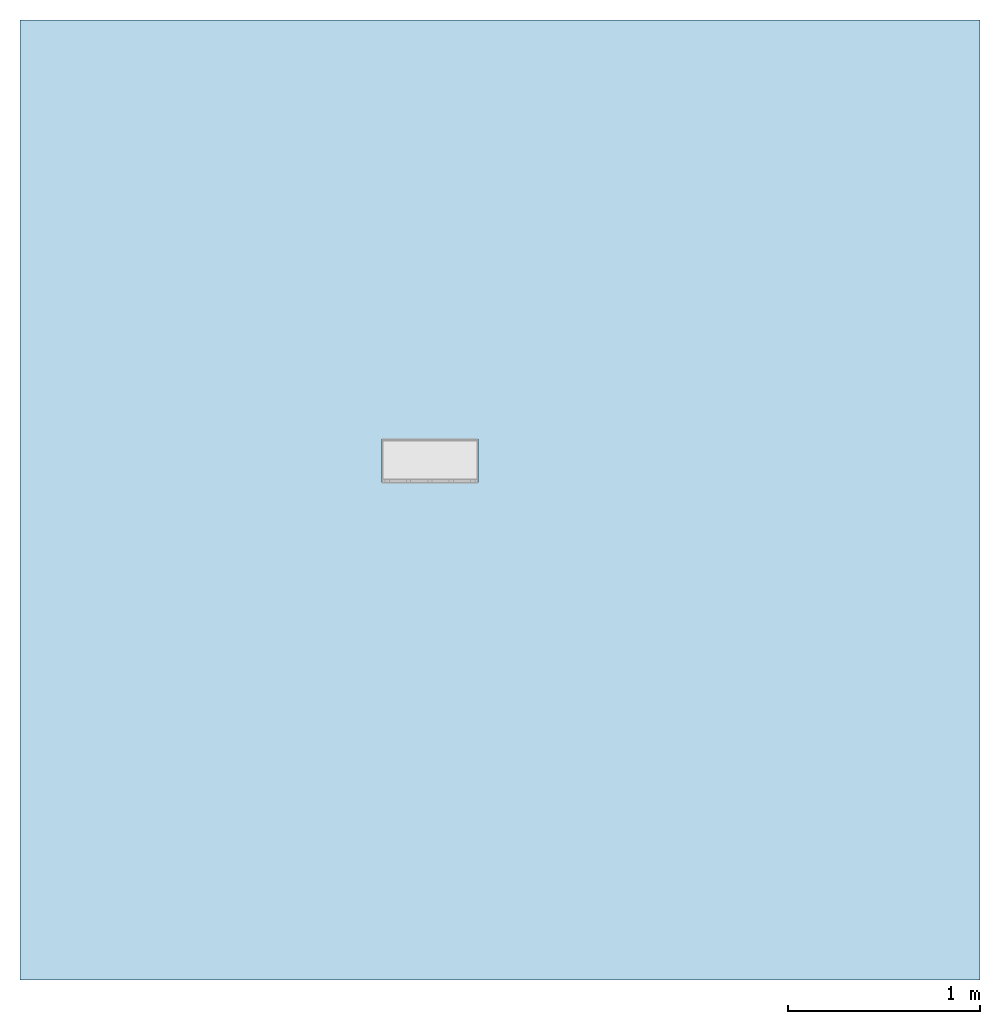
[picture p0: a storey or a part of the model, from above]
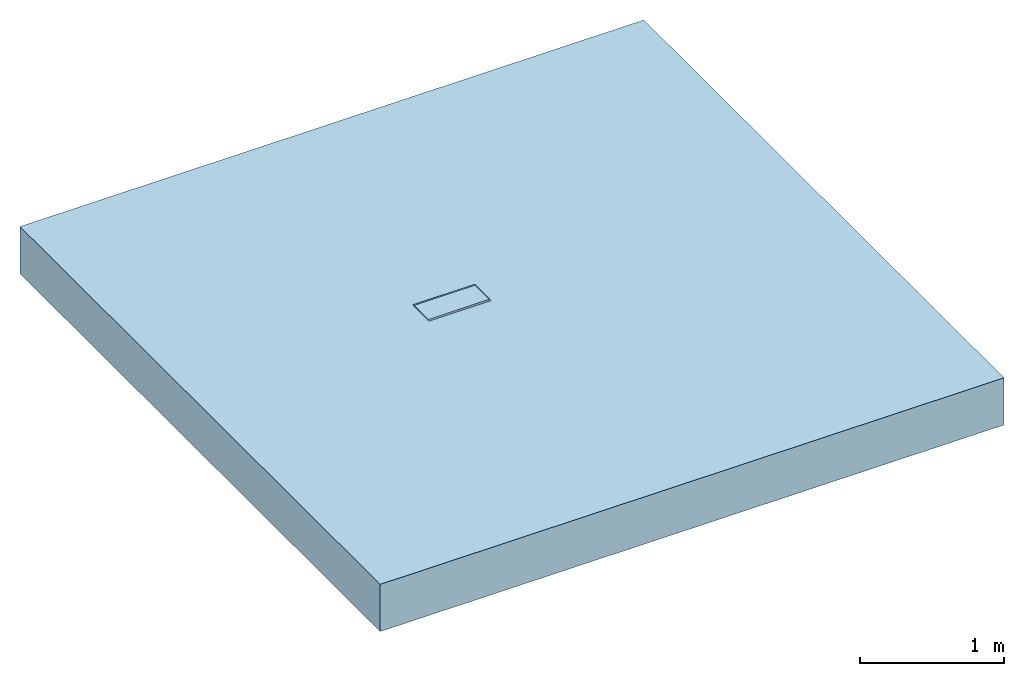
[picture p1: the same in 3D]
Properties of the parts of a building model (IFC2X3)

# File
Description: ViewDefinition [CoordinationView]
File name: 23218 - Universal Sump Unit - 500mm LG.ifc
Time: 2013-10-30T13:50:15
Written by: Autodesk Revit 2013
Made in: 20120221_2030(x64)

# IfcProject, Project Number
LongName: Project Name; Phase: Project Status

# IfcSite, Default
RefLatitude: 42, 21, 30, 344238; RefLongitude: -71, -3, -35, -194702; RefElevation: 0 mm

# IfcBuilding
Pset_BuildingCommon - NumberOfStoreys: 1
Other - Client Name: Owner; Project Name: Project Name; Project Issue Date: Issue Date; Project Number: Project Number; Project Address: ## Street City, State Zip; Project Status: Project Status

# IfcBuildingStorey, Level 1
LongName: Level 1; Elevation: 0 mm
Constraints - Elevation Base: 0; Elevation: 0 mm
Graphics - Color: 0; Symbol at End 1 Default: no; Line Pattern: Center; Symbol: M_Level Head - Circle: M_Level Head - Circle; Line Weight: 1; Symbol at End 2 Default: yes
Dimensions - Computation Height: 0 mm
Identity Data - Structural: no; Name: Level 1; Building Story: yes

# IfcBuildingElementProxy: 23218 - Universal Sump Unit - 500mm LG, Civil-Drainage-Channel-ACO-MultiDrain-M200D-Brickslot-Channel-System:23218 - Universal Sump Unit - 500mm LG:23218 - Universal Sump Unit - 500mm LG:196059
In: Level 1
Material: Plastic, Opaque Black, Steel, Galvanized, Phenolic Resin, Vienite® Synthetic Resin Concrete
Other - CreatedBy: www.aco.co.uk; Revision: 1
Dimensions - Length: 1000 mm; FloorCut_Length: -500 mm; Custom_Void_Length: 500 mm; Volume: 23569804 mm3; Brickslot Access Unit Void Bottom Depth: -105 mm; Brickslot Void Length: -500 mm; Brickslot Grating Void Depth: 6500 mm; Brickslot Access Void Depth: 0 mm; EndCap Position: 500 mm; Length Drain: -1000 mm; FloorCut_Depth: 790 mm; Brickslot Access unit void length: -500 mm; InvDepth: 110 mm; EndCap_Height: 310 mm; FloorCut_HorPosition: 117.5 mm; Depth: 235 mm; FloorCut_Width: 235 mm
Construction - 408995_Load Class C250 & D400_Brickslot Grating_Galvanized Steel_1000mm Long: no; 408997_Load Class C250 & D400_Brickslot_Access Unit_Galvanized Steel_500mm Long: yes; 408996_Load Class C250 & D400_Brickslot Grating_Galvanized Steel_500mm Long: no; 23219 - Universal Endcap (Male End): no; 23219 - Universal Endcap (Female End): no; Constant Depth Channel_500: no; Constant Depth Channel_1000: no; Shallow Depth Channel: no; Shallow Depth Channel with seal: no; 23410_Sump Unit: yes
Constraints - Moves With Nearby Elements: no; Level: Level: Level 1
Phasing - Phase Created: New Construction
Pset_BuildingElementProxyCommon - Reference: 23218 - Universal Sump Unit - 500mm LG
General - TagNumber: 0; SerialNumber: 0
Identity Data - Watermarked By: www.aco.co.uk; Maintenance guidelines: http://www.aco.co.uk/download.php?id=173; Assembly Code: D2040; Product Page URL: http://www.aco.co.uk/product_detail.php?id=58; Model: ACO MultiDrain MD Brickslot - M200D; Product brochure: http://www.aco.co.uk/download.php?id=173; Installation guidelines: http://www.aco.co.uk/download.php?id=173; Fax: +44 (0)1462 815895; Price: POA - contact ACO; OmniClass Title: Rainwater Removal; Watermark 2: This file is water marked and users are prohibited to reproduce, adapt, distribute this information; Watermark 1: This file is the property of ACO Technologies PLC; Address: ACO Business Park, Hitchin Road, Shefford, Bedfordshire, United Kingdom SG17 5TE; Manufacturer: ACO Technologies plc - ACO Water Management Division; Product Code: 23218; Assembly Description: Rain Water Drainage; Watermarked With: BIM Manager Premium Suite; URL: www.aco.co.uk; e-mail Sales: customersupport@aco.co.uk; Cost: 0; e-mail Technical: technical@aco.co.uk; Telephone: +44 (0)1462 816666; Model Description: Channel drainage system; Type Comments: ACO MultiDrain M200D Sump Unit 500mm Long; OmniClass Number: 23.70.50.24
Data - Pre-formed Outlet Ø: 110mm/160mm/200mm; Product Standard: BS EN 1433:2002, CE marked; ACO Hydraulic Design Software: http://www.acodesign.co.uk; Product Dimensions: 500mm x 235mm x 790mm (LxWxH); Product Weight: 47.0 Kg; Load Class: A 15 - D 400; Installation - Concrete Grade: N/A; Channel C.S.A: N/A; Concrete Surround Volume - Load Class B 125 - C 250 - Concrete Pavement: N/A; Hydraulic Performance: http://www.aco.co.uk/download.php?id=173; Concrete Surround Volume - Load Class A 15 - Concrete Pavement: N/A; Concrete Surround Volume - Load Class D 400 - Concrete Pavement: N/A; Invert Depth: 765mm
Green Building Properties - Channel Recyclable: Fully recyclable; Edge Rail Recycled Material Content: Between 40% - 90%; Channel Recycled Material Content: 20% minimum; Edge Rail Recyclable: Fully recyclable
Materials and Finishes - Channel Colour: Brown; Edge Rail Finish: Pre-galvanised; Channel Material: Vienite® Synthetic Resin Concrete; Edge Rail Colour: Silver; Edge Rail Material: Steel
Model Properties - Brickslot Grating Product code 408995: N/A; End Cap Product code 23219: N/A; Brickslot Grating Product code 408996: N/A; Brickslot Access Unit Product code 408997: Load Class C250/D400 - Brickslot Access Unit Galvanised Steel - 500mm long x 105mm high - 10mm Slot - Intake area - 10000mm²/m 8.5 Kg

# IfcOpeningElement: Opening (2)
In: Level 1
Dimensions - Area: 24983618 mm2; Volume: 9963617390 mm3; Thickness: 400 mm; Perimeter: 20000 mm
Constraints - Level: Level: Level 1; Related to Mass: no; Room Bounding: yes; Height Offset From Level: 0 mm
Phasing - Phase Created: New Construction
Structural - Structural: no; Enable Analytical Model: no
Analytical Properties - Heat Transfer Coefficient (U): 2.0925; Thermal Resistance (R): 0.477897; Thermal mass: 543920; Absorptance: 0.1; Roughness: 1
Construction - Default Thickness: 400 mm; Function: 0
Graphics - Coarse Scale Fill Color: 0
Materials and Finishes - Structural Material: Earth

# IfcSlab: Floor:Generic Floor - 400mm, Floor:Generic Floor - 400mm:193825
In: Level 1
PredefinedType: FLOOR; Material: Earth 400 mm
Dimensions - Area: 24983618 mm2; Volume: 9963617390 mm3; Thickness: 400 mm; Perimeter: 20000 mm
Constraints - Level: Level: Level 1; Related to Mass: no; Room Bounding: yes; Height Offset From Level: 0 mm
Phasing - Phase Created: New Construction
Structural - Structural: no; Enable Analytical Model: no
Pset_SlabCommon - Reference: Generic Floor - 400mm; IsExternal: no; LoadBearing: yes
Analytical Properties - Heat Transfer Coefficient (U): 2.0925; Thermal Resistance (R): 0.477897; Thermal mass: 543920; Absorptance: 0.1; Roughness: 1
Construction - Default Thickness: 400 mm; Function: 0
Graphics - Coarse Scale Fill Color: 0
Materials and Finishes - Structural Material: Earth
